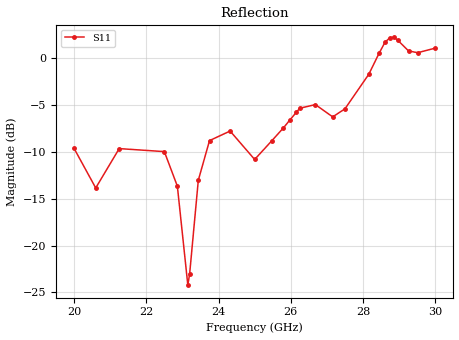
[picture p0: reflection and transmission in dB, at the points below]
! freq	mag(S11)	phase(S11)
!ADF5904 RF4
#  Hz  S  MA  R 50
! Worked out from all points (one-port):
!   1001 points, 20 GHz to 30 GHz, reference 50 ohm
!   lowest |S11| = -24.2 dB at 23.15 GHz (marker M1), VSWR 1.13, Z = 44.4 - j1.36 ohm
!   |S11| at or under -10 dB: 20.06 GHz to 21.15 GHz (1.088 GHz wide, 5.28 % of centre); 22.51 GHz to 23.62 GHz (1.108 GHz wide, 4.8 % of centre); 24.74 GHz to 25.25 GHz (509.1 MHz wide, 2.04 % of centre)
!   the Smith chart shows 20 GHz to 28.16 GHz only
!   S11 on the Smith chart (normalised r, x): 20 GHz: 0.98, +0.69; 23.2 GHz: 0.91, -0.10; 26.15 GHz: 0.46, -0.62; 27.16 GHz: 2.44, +0.98; 28.16 GHz: 0.12, +0.47
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2e10  0.3305 72.0
2.06e10  0.2032 34.9
2.125e10  0.3296 17.4
2.25e10  0.3176 80.0
2.286e10  0.2077 103.2
2.315e10  0.06156 -165.6
2.32e10  0.07065 -126.3
2.344e10  0.2234 -64.0
2.375e10  0.3636 -31.8
2.432e10  0.409 13.1
2.5e10  0.2884 83.8
2.548e10  0.3639 133.4
2.579e10  0.4238 179.6
2.597e10  0.4672 -144.6
2.615e10  0.514 -108.3
2.625e10  0.5412 -90.5
2.668e10  0.5662 -36.1
2.716e10  0.4868 18.4
2.75e10  0.5374 70.1
2.816e10  0.8219 129.0
2.845e10  1.069 160.8
2.861e10  1.219 -172.4
2.875e10  1.291 -146.0
2.886e10  1.293 -124.8
2.896e10  1.249 -106.3
2.926e10  1.095 -63.9
2.951e10  1.071 -42.2
3e10  1.133 -11.5
